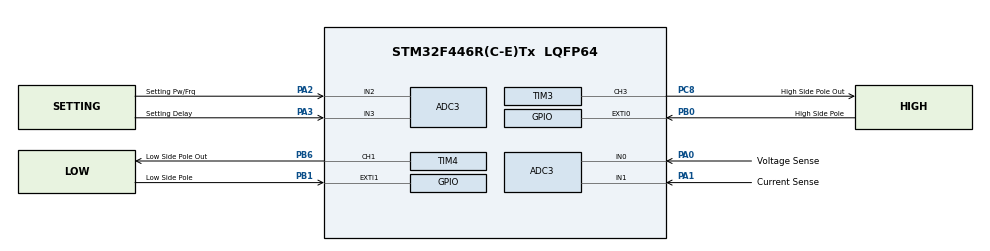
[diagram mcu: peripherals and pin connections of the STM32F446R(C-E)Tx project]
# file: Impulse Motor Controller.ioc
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ADC3.Channel-0\#ChannelRegularConversion=ADC_CHANNEL_0
ADC3.Channel-1\#ChannelRegularConversion=ADC_CHANNEL_1
ADC3.Channel-2\#ChannelRegularConversion=ADC_CHANNEL_2
ADC3.Channel-3\#ChannelRegularConversion=ADC_CHANNEL_3
ADC3.ContinuousConvMode=ENABLE
ADC3.EOCSelection=ADC_EOC_SEQ_CONV
ADC3.NbrOfConversion=4
ADC3.NbrOfConversionFlag=1
ADC3.Rank-0\#ChannelRegularConversion=1
ADC3.Rank-1\#ChannelRegularConversion=2
ADC3.Rank-2\#ChannelRegularConversion=3
ADC3.Rank-3\#ChannelRegularConversion=4
ADC3.SamplingTime-0\#ChannelRegularConversion=ADC_SAMPLETIME_15CYCLES
ADC3.SamplingTime-1\#ChannelRegularConversion=ADC_SAMPLETIME_15CYCLES
ADC3.SamplingTime-2\#ChannelRegularConversion=ADC_SAMPLETIME_15CYCLES
ADC3.SamplingTime-3\#ChannelRegularConversion=ADC_SAMPLETIME_15CYCLES
Dma.ADC3.0.Direction=DMA_PERIPH_TO_MEMORY
Dma.ADC3.0.FIFOMode=DMA_FIFOMODE_DISABLE
Dma.ADC3.0.Instance=DMA2_Stream0
Dma.ADC3.0.MemDataAlignment=DMA_MDATAALIGN_HALFWORD
Dma.ADC3.0.MemInc=DMA_MINC_ENABLE
Dma.ADC3.0.Mode=DMA_CIRCULAR
Dma.ADC3.0.PeriphDataAlignment=DMA_PDATAALIGN_HALFWORD
Dma.ADC3.0.PeriphInc=DMA_PINC_DISABLE
Dma.ADC3.0.Priority=DMA_PRIORITY_MEDIUM
Dma.Request0=ADC3
Mcu.Family=STM32F4
Mcu.Name=STM32F446R(C-E)Tx
Mcu.Package=LQFP64
NVIC.DMA2_Stream0_IRQn=true\:0\:0\:false\:false\:true\:false\:true\:true
NVIC.EXTI0_IRQn=true\:0\:0\:false\:false\:true\:true\:true\:true
NVIC.EXTI1_IRQn=true\:0\:0\:false\:false\:true\:true\:true\:true
NVIC.PriorityGroup=NVIC_PRIORITYGROUP_4
PA0-WKUP.GPIO_Label=Voltage Sense
PA0-WKUP.Signal=ADCx_IN0
PA1.GPIO_Label=Current Sense
PA1.Signal=ADCx_IN1
PA2.GPIO_Label=Setting Pw/Frq
PA2.Signal=ADCx_IN2
PA3.GPIO_Label=Setting Delay
PA3.Signal=ADCx_IN3
PB0.GPIO_Label=High Side Pole
PB0.GPIO_ModeDefaultEXTI=GPIO_MODE_IT_FALLING
PB0.Signal=GPXTI0
PB1.GPIO_Label=Low Side Pole
PB1.GPIO_ModeDefaultEXTI=GPIO_MODE_IT_FALLING
PB1.Signal=GPXTI1
PB6.GPIO_Label=Low Side Pole Out
PB6.GPIO_Speed=GPIO_SPEED_FREQ_VERY_HIGH
PB6.Signal=S_TIM4_CH1
PC8.GPIO_Label=High Side Pole Out
PC8.GPIO_Speed=GPIO_SPEED_FREQ_VERY_HIGH
PC8.Signal=S_TIM3_CH3
ProjectManager.HeapSize=0x200
ProjectManager.StackSize=0x400
ProjectManager.TargetToolchain=MDK-ARM V5.32
RCC.CortexFreq_Value=16000000
RCC.USBFreq_Value=96000000
RCC.VCOOutputFreq_Value=192000000
SH.ADCx_IN0.0=ADC3_IN0,IN0
SH.ADCx_IN1.0=ADC3_IN1,IN1
SH.ADCx_IN2.0=ADC3_IN2,IN2
SH.ADCx_IN3.0=ADC3_IN3,IN3
SH.S_TIM3_CH3.0=TIM3_CH3,PWM Generation3 CH3
SH.S_TIM4_CH1.0=TIM4_CH1,PWM Generation1 CH1
TIM3.AutoReloadPreload=TIM_AUTORELOAD_PRELOAD_ENABLE
TIM3.Channel-PWM\ Generation3\ CH3=TIM_CHANNEL_3
TIM3.OC3Preload_PWM=ENABLE
TIM3.OCMode_PWM-PWM\ Generation3\ CH3=TIM_OCMODE_PWM1
TIM3.OCPolarity_3=TIM_OCPOLARITY_LOW
TIM3.Period=65535
TIM3.Prescaler=180-1
TIM3.Pulse-PWM\ Generation3\ CH3=1
TIM4.AutoReloadPreload=TIM_AUTORELOAD_PRELOAD_ENABLE
TIM4.Channel-PWM\ Generation1\ CH1=TIM_CHANNEL_1
TIM4.OC1Preload_PWM=ENABLE
TIM4.OCMode_PWM-PWM\ Generation1\ CH1=TIM_OCMODE_PWM1
TIM4.OCPolarity_1=TIM_OCPOLARITY_LOW
TIM4.Period=65535
TIM4.Prescaler=180-1
TIM4.Pulse-PWM\ Generation1\ CH1=1
TIM5.AutoReloadPreload=TIM_AUTORELOAD_PRELOAD_ENABLE
TIM5.Prescaler=180-1
VP_TIM3_VS_ClockSourceINT.Mode=Internal
VP_TIM3_VS_OPM.Mode=OPM_bit
VP_TIM4_VS_ClockSourceINT.Mode=Internal
VP_TIM4_VS_OPM.Mode=OPM_bit
VP_TIM5_VS_ClockSourceINT.Mode=Internal
board=custom

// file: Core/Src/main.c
/* USER CODE BEGIN Header */
/**
  ******************************************************************************
  * @file           : main.c
  * @brief          : Main program body
  ******************************************************************************
  * @attention
  *
  * Copyright (c) 2023 STMicroelectronics.
  * All rights reserved.
  *
  * This software is licensed under terms that can be found in the LICENSE file
  * in the root directory of this software component.
  * If no LICENSE file comes with this software, it is provided AS-IS.
  *
  ******************************************************************************
  */
/* USER CODE END Header */
#include "main.h"

ADC_HandleTypeDef hadc3;
DMA_HandleTypeDef hdma_adc3;

TIM_HandleTypeDef htim3;
TIM_HandleTypeDef htim4;
TIM_HandleTypeDef htim5;

/* USER CODE BEGIN PV */

uint32_t cycleTime;
uint32_t halfTime;

uint32_t pulseDelay = 0;
uint32_t pulseWidth = 1000;

int highPulseState;
int lowPulseState;

float uniPolePass = 3.0;
float rpmPulse;
float hertzPulse;

uint32_t delaySetpoint = 0;
uint32_t widthSetpoint = 1000;

int motorEnable;
int motorRunning;
int prevMotorEnable;

float rpmSetPulse = 500;
float rpmSetPulsePrev;
float rpmActSetPulse = 500;
float rpmPulseIncremental;
float rpmPulseAttackTime = 100;

float error;
float cumError;
float rateError;
float lastError;
float multiplierPid;
float kp = 3.0;
float ki = 0.00045;
float kd = 0.01;
float PID_MIN = 1.0;
float PID_MAX = 1000.0;

int incrementalPulseDone;
int motorAtSpeed;

int pidEnable = 1;
/* USER CODE END PV */

void SystemClock_Config(void);
static void MX_GPIO_Init(void);
static void MX_DMA_Init(void);
static void MX_TIM3_Init(void);
static void MX_TIM4_Init(void);
static void MX_TIM5_Init(void);
static void MX_ADC3_Init(void);

int main(void)
{

  /* MCU Configuration--------------------------------------------------------*/

  /* Reset of all peripherals, Initializes the Flash interface and the Systick. */
  HAL_Init();

  /* Configure the system clock */
  SystemClock_Config();

  /* Initialize all configured peripherals */
  MX_GPIO_Init();
  MX_DMA_Init();
  MX_TIM3_Init();
  MX_TIM4_Init();
  MX_TIM5_Init();
  MX_ADC3_Init();
  /* USER CODE BEGIN 2 */

	HAL_TIM_Base_Start(&htim5);
		GPIOC->BSRR |= (1<<6);
		//GPIOC->BSRR |= (1<<6) <<16;
  /* USER CODE END 2 */

  /* Infinite loop */
  while (1)
  {

    /* USER CODE BEGIN 3 */

		if((motorEnable == 1) && (prevMotorEnable == 0)){
			GPIOC->BSRR |= (1<<6) <<16;
			pulseWidth = 500;
			TIM5->CNT = 0;
			prevMotorEnable = 1;
			rpmActSetPulse = rpmSetPulse / 3;
		}
		else if((motorEnable == 0) && (prevMotorEnable == 1)){
			GPIOC->BSRR |= (1<<6);
			prevMotorEnable = 0;
			lowPulseState = 0;
			highPulseState = 0;
			cycleTime = 0;
			halfTime = 0;
		}

		if(motorEnable == 0){
			rpmActSetPulse = 0;
		}

		if((highPulseState == 1) && (TIM5->CNT >= pulseDelay)){
			incrementalPulseDone = 0;
			highPulseState = 2;
			TIM3->ARR = pulseWidth;
			__HAL_TIM_ENABLE(&htim3);
		}

		if((lowPulseState == 1) && (TIM5->CNT >= (pulseDelay + halfTime))){
			lowPulseState = 2;
			TIM4->ARR = pulseWidth;
			__HAL_TIM_ENABLE(&htim4);
		}

		if((motorRunning == 0)){
			if((TIM5->CNT > 1000) && (motorEnable == 1)){
				cycleTime = 400000;
				highPulseState = 1;
				halfTime = 200000;
				lowPulseState = 1;
			}

			if(TIM5->CNT > 400000){
				TIM5->CNT = 0;
			}
		}

		if((hertzPulse > 2.0) && (motorEnable == 1)){
			motorRunning = 1;
			pulseWidth = 1000;
		}
		else{
			motorRunning = 0;
		}

		if((pidEnable == 1) && (motorEnable == 1) && (motorRunning == 1) && ((highPulseState == 2) || (lowPulseState == 2))){
			error = (rpmActSetPulse - rpmPulse); // determine error
			cumError += error; // compute integral
			rateError = (error - lastError);
			multiplierPid = kp*error + ki*cumError + kd*rateError;
			lastError = error;

			if(multiplierPid > PID_MAX){
				multiplierPid = PID_MAX;
			}
			else if(multiplierPid < PID_MIN){
				multiplierPid = PID_MIN;
			}
		}
		else if((pidEnable == 0) || (motorEnable == 0)){
			error = 0.0;
			cumError = 0.0;
			rateError = 0.0;
			lastError = 0.0;
			multiplierPid = 800.0;
		}
		if((highPulseState == 0) && (lowPulseState == 0)){
			if(cycleTime > 0){
				if(TIM5->CNT >= 2000000){
					hertzPulse = 0.0;
				}
				else{
					hertzPulse = (1000000.0 / (float) cycleTime);
				}
				rpmPulse = (hertzPulse / uniPolePass)  * 60.0;
				pulseDelay = ((((float) cycleTime / 2.0) / 1000.0) * (float) delaySetpoint);
				pulseWidth = (uint32_t) (((((((float) cycleTime / 2.0) / 1000.0) * (float) widthSetpoint) / 2.0) / 1000.0) * (float)multiplierPid);
				if(pulseWidth > 65535){
					pulseWidth = 65534;
				}
			}
			else{
				rpmPulse = 0.0;
			}

		}
		if((rpmSetPulse != rpmSetPulsePrev)){
			rpmSetPulsePrev = rpmSetPulse;
			motorAtSpeed = 0;

			if(rpmSetPulse > rpmActSetPulse){
				rpmPulseIncremental = (rpmSetPulse - rpmActSetPulse) / rpmPulseAttackTime;
			}
			else if(rpmSetPulse < rpmActSetPulse){
				rpmPulseIncremental = (rpmActSetPulse - rpmSetPulse) / rpmPulseAttackTime;
			}
		}

		if((TIM5->CNT >= 500) && (incrementalPulseDone == 0)){
			incrementalPulseDone = 1;
			if((rpmSetPulse > (rpmActSetPulse * 1.02)) && (motorAtSpeed == 0)){
				rpmActSetPulse += rpmPulseIncremental;
			}
			else if((rpmSetPulse < (rpmActSetPulse * 0.98)) && (motorAtSpeed == 0)){
				rpmActSetPulse -= rpmPulseIncremental;
			}
			else{
				rpmActSetPulse = rpmSetPulse;
				motorAtSpeed = 1;
			}
		}

	//	if((rpmSetPulse < rpmActSetPulse) && (lowPulseState > 1)){
	//		rpmActSetPulse--;
	//		rpmActSetPulse--;
	//	}
//		else if((rpmSetPulse > rpmActSetPulse) && (highPulseState > 1)){
//			rpmActSetPulse++;
//			rpmActSetPulse++;
//		}

		if(highPulseState == 2){
			highPulseState = 0;
		}
		if(lowPulseState == 2){
			lowPulseState = 0;
		}

  }
  /* USER CODE END 3 */
}

void SystemClock_Config(void)
{
  RCC_OscInitTypeDef RCC_OscInitStruct = {0};
  RCC_ClkInitTypeDef RCC_ClkInitStruct = {0};

  /** Configure the main internal regulator output voltage
  */
  __HAL_RCC_PWR_CLK_ENABLE();
  __HAL_PWR_VOLTAGESCALING_CONFIG(PWR_REGULATOR_VOLTAGE_SCALE1);

  /** Initializes the RCC Oscillators according to the specified parameters
  * in the RCC_OscInitTypeDef structure.
  */
  RCC_OscInitStruct.OscillatorType = RCC_OSCILLATORTYPE_HSI;
  RCC_OscInitStruct.HSIState = RCC_HSI_ON;
  RCC_OscInitStruct.HSICalibrationValue = RCC_HSICALIBRATION_DEFAULT;
  RCC_OscInitStruct.PLL.PLLState = RCC_PLL_ON;
  RCC_OscInitStruct.PLL.PLLSource = RCC_PLLSOURCE_HSI;
  RCC_OscInitStruct.PLL.PLLM = 8;
  RCC_OscInitStruct.PLL.PLLN = 180;
  RCC_OscInitStruct.PLL.PLLP = RCC_PLLP_DIV2;
  RCC_OscInitStruct.PLL.PLLQ = 2;
  RCC_OscInitStruct.PLL.PLLR = 2;
  if (HAL_RCC_OscConfig(&RCC_OscInitStruct) != HAL_OK)
  {
    Error_Handler();
  }

  /** Activate the Over-Drive mode
  */
  if (HAL_PWREx_EnableOverDrive() != HAL_OK)
  {
    Error_Handler();
  }

  /** Initializes the CPU, AHB and APB buses clocks
  */
  RCC_ClkInitStruct.ClockType = RCC_CLOCKTYPE_HCLK|RCC_CLOCKTYPE_SYSCLK
                              |RCC_CLOCKTYPE_PCLK1|RCC_CLOCKTYPE_PCLK2;
  RCC_ClkInitStruct.SYSCLKSource = RCC_SYSCLKSOURCE_PLLCLK;
  RCC_ClkInitStruct.AHBCLKDivider = RCC_SYSCLK_DIV1;
  RCC_ClkInitStruct.APB1CLKDivider = RCC_HCLK_DIV4;
  RCC_ClkInitStruct.APB2CLKDivider = RCC_HCLK_DIV2;

  if (HAL_RCC_ClockConfig(&RCC_ClkInitStruct, FLASH_LATENCY_5) != HAL_OK)
  {
    Error_Handler();
  }
}

static void MX_ADC3_Init(void)
{

  ADC_ChannelConfTypeDef sConfig = {0};

  /** Configure the global features of the ADC (Clock, Resolution, Data Alignment and number of conversion)
  */
  hadc3.Instance = ADC3;
  hadc3.Init.ClockPrescaler = ADC_CLOCK_SYNC_PCLK_DIV4;
  hadc3.Init.Resolution = ADC_RESOLUTION_12B;
  hadc3.Init.ScanConvMode = ENABLE;
  hadc3.Init.ContinuousConvMode = ENABLE;
  hadc3.Init.DiscontinuousConvMode = DISABLE;
  hadc3.Init.ExternalTrigConvEdge = ADC_EXTERNALTRIGCONVEDGE_NONE;
  hadc3.Init.ExternalTrigConv = ADC_SOFTWARE_START;
  hadc3.Init.DataAlign = ADC_DATAALIGN_RIGHT;
  hadc3.Init.NbrOfConversion = 4;
  hadc3.Init.DMAContinuousRequests = DISABLE;
  hadc3.Init.EOCSelection = ADC_EOC_SEQ_CONV;
  if (HAL_ADC_Init(&hadc3) != HAL_OK)
  {
    Error_Handler();
  }

  /** Configure for the selected ADC regular channel its corresponding rank in the sequencer and its sample time.
  */
  sConfig.Channel = ADC_CHANNEL_0;
  sConfig.Rank = 1;
  sConfig.SamplingTime = ADC_SAMPLETIME_15CYCLES;
  if (HAL_ADC_ConfigChannel(&hadc3, &sConfig) != HAL_OK)
  {
    Error_Handler();
  }

  /** Configure for the selected ADC regular channel its corresponding rank in the sequencer and its sample time.
  */
  sConfig.Channel = ADC_CHANNEL_1;
  sConfig.Rank = 2;
  if (HAL_ADC_ConfigChannel(&hadc3, &sConfig) != HAL_OK)
  {
    Error_Handler();
  }

  /** Configure for the selected ADC regular channel its corresponding rank in the sequencer and its sample time.
  */
  sConfig.Channel = ADC_CHANNEL_2;
  sConfig.Rank = 3;
  if (HAL_ADC_ConfigChannel(&hadc3, &sConfig) != HAL_OK)
  {
    Error_Handler();
  }

  /** Configure for the selected ADC regular channel its corresponding rank in the sequencer and its sample time.
  */
  sConfig.Channel = ADC_CHANNEL_3;
  sConfig.Rank = 4;
  if (HAL_ADC_ConfigChannel(&hadc3, &sConfig) != HAL_OK)
  {
    Error_Handler();
  }

}

static void MX_TIM3_Init(void)
{

  TIM_ClockConfigTypeDef sClockSourceConfig = {0};
  TIM_MasterConfigTypeDef sMasterConfig = {0};
  TIM_OC_InitTypeDef sConfigOC = {0};

  htim3.Instance = TIM3;
  htim3.Init.Prescaler = 180-1;
  htim3.Init.CounterMode = TIM_COUNTERMODE_UP;
  htim3.Init.Period = 65535;
  htim3.Init.ClockDivision = TIM_CLOCKDIVISION_DIV1;
  htim3.Init.AutoReloadPreload = TIM_AUTORELOAD_PRELOAD_ENABLE;
  if (HAL_TIM_Base_Init(&htim3) != HAL_OK)
  {
    Error_Handler();
  }
  sClockSourceConfig.ClockSource = TIM_CLOCKSOURCE_INTERNAL;
  if (HAL_TIM_ConfigClockSource(&htim3, &sClockSourceConfig) != HAL_OK)
  {
    Error_Handler();
  }
  if (HAL_TIM_PWM_Init(&htim3) != HAL_OK)
  {
    Error_Handler();
  }
  if (HAL_TIM_OnePulse_Init(&htim3, TIM_OPMODE_SINGLE) != HAL_OK)
  {
    Error_Handler();
  }
  sMasterConfig.MasterOutputTrigger = TIM_TRGO_RESET;
  sMasterConfig.MasterSlaveMode = TIM_MASTERSLAVEMODE_DISABLE;
  if (HAL_TIMEx_MasterConfigSynchronization(&htim3, &sMasterConfig) != HAL_OK)
  {
    Error_Handler();
  }
  sConfigOC.OCMode = TIM_OCMODE_PWM1;
  sConfigOC.Pulse = 1;
  sConfigOC.OCPolarity = TIM_OCPOLARITY_LOW;
  sConfigOC.OCFastMode = TIM_OCFAST_DISABLE;
  if (HAL_TIM_PWM_ConfigChannel(&htim3, &sConfigOC, TIM_CHANNEL_3) != HAL_OK)
  {
    Error_Handler();
  }
  /* USER CODE BEGIN TIM3_Init 2 */

	TIM_CCxChannelCmd(htim3.Instance, TIM_CHANNEL_3,TIM_CCx_ENABLE);
	__HAL_TIM_CLEAR_IT(&htim3, TIM_IT_UPDATE);
	__HAL_TIM_ENABLE_IT(&htim3, TIM_IT_UPDATE);
  /* USER CODE END TIM3_Init 2 */
  HAL_TIM_MspPostInit(&htim3);

}

static void MX_TIM4_Init(void)
{

  TIM_ClockConfigTypeDef sClockSourceConfig = {0};
  TIM_MasterConfigTypeDef sMasterConfig = {0};
  TIM_OC_InitTypeDef sConfigOC = {0};

  htim4.Instance = TIM4;
  htim4.Init.Prescaler = 180-1;
  htim4.Init.CounterMode = TIM_COUNTERMODE_UP;
  htim4.Init.Period = 65535;
  htim4.Init.ClockDivision = TIM_CLOCKDIVISION_DIV1;
  htim4.Init.AutoReloadPreload = TIM_AUTORELOAD_PRELOAD_ENABLE;
  if (HAL_TIM_Base_Init(&htim4) != HAL_OK)
  {
    Error_Handler();
  }
  sClockSourceConfig.ClockSource = TIM_CLOCKSOURCE_INTERNAL;
  if (HAL_TIM_ConfigClockSource(&htim4, &sClockSourceConfig) != HAL_OK)
  {
    Error_Handler();
  }
  if (HAL_TIM_PWM_Init(&htim4) != HAL_OK)
  {
    Error_Handler();
  }
  if (HAL_TIM_OnePulse_Init(&htim4, TIM_OPMODE_SINGLE) != HAL_OK)
  {
    Error_Handler();
  }
  sMasterConfig.MasterOutputTrigger = TIM_TRGO_RESET;
  sMasterConfig.MasterSlaveMode = TIM_MASTERSLAVEMODE_DISABLE;
  if (HAL_TIMEx_MasterConfigSynchronization(&htim4, &sMasterConfig) != HAL_OK)
  {
    Error_Handler();
  }
  sConfigOC.OCMode = TIM_OCMODE_PWM1;
  sConfigOC.Pulse = 1;
  sConfigOC.OCPolarity = TIM_OCPOLARITY_LOW;
  sConfigOC.OCFastMode = TIM_OCFAST_DISABLE;
  if (HAL_TIM_PWM_ConfigChannel(&htim4, &sConfigOC, TIM_CHANNEL_1) != HAL_OK)
  {
    Error_Handler();
  }
  /* USER CODE BEGIN TIM4_Init 2 */

	TIM_CCxChannelCmd(htim4.Instance, TIM_CHANNEL_1,TIM_CCx_ENABLE);
	__HAL_TIM_CLEAR_IT(&htim4, TIM_IT_UPDATE);
	__HAL_TIM_ENABLE_IT(&htim4, TIM_IT_UPDATE);
  /* USER CODE END TIM4_Init 2 */
  HAL_TIM_MspPostInit(&htim4);

}

static void MX_TIM5_Init(void)
{

  TIM_ClockConfigTypeDef sClockSourceConfig = {0};
  TIM_MasterConfigTypeDef sMasterConfig = {0};

  htim5.Instance = TIM5;
  htim5.Init.Prescaler = 90-1;
  htim5.Init.CounterMode = TIM_COUNTERMODE_UP;
  htim5.Init.Period = 4294967295;
  htim5.Init.ClockDivision = TIM_CLOCKDIVISION_DIV1;
  htim5.Init.AutoReloadPreload = TIM_AUTORELOAD_PRELOAD_ENABLE;
  if (HAL_TIM_Base_Init(&htim5) != HAL_OK)
  {
    Error_Handler();
  }
  sClockSourceConfig.ClockSource = TIM_CLOCKSOURCE_INTERNAL;
  if (HAL_TIM_ConfigClockSource(&htim5, &sClockSourceConfig) != HAL_OK)
  {
    Error_Handler();
  }
  sMasterConfig.MasterOutputTrigger = TIM_TRGO_RESET;
  sMasterConfig.MasterSlaveMode = TIM_MASTERSLAVEMODE_DISABLE;
  if (HAL_TIMEx_MasterConfigSynchronization(&htim5, &sMasterConfig) != HAL_OK)
  {
    Error_Handler();
  }

}

static void MX_DMA_Init(void)
{

  /* DMA controller clock enable */
  __HAL_RCC_DMA2_CLK_ENABLE();

  /* DMA interrupt init */
  /* DMA2_Stream0_IRQn interrupt configuration */
  HAL_NVIC_SetPriority(DMA2_Stream0_IRQn, 0, 0);
  HAL_NVIC_EnableIRQ(DMA2_Stream0_IRQn);

}

static void MX_GPIO_Init(void)
{
  GPIO_InitTypeDef GPIO_InitStruct = {0};

  /* GPIO Ports Clock Enable */
  __HAL_RCC_GPIOA_CLK_ENABLE();
  __HAL_RCC_GPIOB_CLK_ENABLE();
  __HAL_RCC_GPIOC_CLK_ENABLE();

  /*Configure GPIO pin Output Level */
  HAL_GPIO_WritePin(motorEnable_GPIO_Port, motorEnable_Pin, GPIO_PIN_SET);

  /*Configure GPIO pins : High_Side_Pole_Pin Low_Side_Pole_Pin */
  GPIO_InitStruct.Pin = High_Side_Pole_Pin|Low_Side_Pole_Pin;
  GPIO_InitStruct.Mode = GPIO_MODE_IT_FALLING;
  GPIO_InitStruct.Pull = GPIO_NOPULL;
  HAL_GPIO_Init(GPIOB, &GPIO_InitStruct);

  /*Configure GPIO pin : motorEnable_Pin */
  GPIO_InitStruct.Pin = motorEnable_Pin;
  GPIO_InitStruct.Mode = GPIO_MODE_OUTPUT_PP;
  GPIO_InitStruct.Pull = GPIO_NOPULL;
  GPIO_InitStruct.Speed = GPIO_SPEED_FREQ_LOW;
  HAL_GPIO_Init(motorEnable_GPIO_Port, &GPIO_InitStruct);

  /* EXTI interrupt init*/
  HAL_NVIC_SetPriority(EXTI0_IRQn, 0, 0);
  HAL_NVIC_EnableIRQ(EXTI0_IRQn);

  HAL_NVIC_SetPriority(EXTI1_IRQn, 0, 0);
  HAL_NVIC_EnableIRQ(EXTI1_IRQn);

}

void Error_Handler(void)
{
  __disable_irq();
  while (1)
  {
  }
}
